VERSION 5.8 ;
BUSBITCHARS "[]" ;
DIVIDERCHAR "/" ;

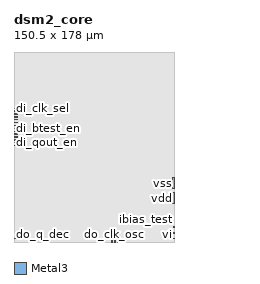
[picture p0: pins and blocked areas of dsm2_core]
MACRO dsm2_core
  CLASS BLOCK ;
  FOREIGN dsm2_core 0 0 ;
  ORIGIN 0 0 ;
  SIZE 150.5 BY 178 ;
  PIN di_btest_en
    DIRECTION INPUT ;
    USE SIGNAL ;
    PORT
      LAYER Metal3 ;
        RECT 0 106.305 3 106.595 ;
    END
  END di_btest_en
  PIN di_clk
    DIRECTION INPUT ;
    USE CLOCK ;
    PORT
      LAYER Metal3 ;
        RECT 97.125 0 97.415 1 ;
    END
  END di_clk
  PIN di_clk_sel
    DIRECTION INPUT ;
    USE SIGNAL ;
    PORT
      LAYER Metal3 ;
        RECT 0 125.135 3 125.425 ;
    END
  END di_clk_sel
  PIN di_dith_amp[0]
    DIRECTION INPUT ;
    USE SIGNAL ;
    PORT
      LAYER Metal3 ;
        RECT 0 103.615 3 103.905 ;
    END
  END di_dith_amp[0]
  PIN di_dith_amp[1]
    DIRECTION INPUT ;
    USE SIGNAL ;
    PORT
      LAYER Metal3 ;
        RECT 0 100.925 3 101.215 ;
    END
  END di_dith_amp[1]
  PIN di_dith_en
    DIRECTION INPUT ;
    USE SIGNAL ;
    PORT
      LAYER Metal3 ;
        RECT 0 98.235 3 98.525 ;
    END
  END di_dith_en
  PIN di_ena
    DIRECTION INPUT ;
    USE SIGNAL ;
    PORT
      LAYER Metal3 ;
        RECT 0 119.755 3 120.045 ;
    END
  END di_ena
  PIN di_osc_en
    DIRECTION INPUT ;
    USE SIGNAL ;
    PORT
      LAYER Metal3 ;
        RECT 0 122.445 3 122.735 ;
    END
  END di_osc_en
  PIN di_qout_en
    DIRECTION INPUT ;
    USE SIGNAL ;
    PORT
      LAYER Metal3 ;
        RECT 0 92.855 3 93.145 ;
    END
  END di_qout_en
  PIN di_rst_b
    DIRECTION INPUT ;
    USE SIGNAL ;
    PORT
      LAYER Metal3 ;
        RECT 0 95.545 3 95.835 ;
    END
  END di_rst_b
  PIN di_trim[0]
    DIRECTION INPUT ;
    USE SIGNAL ;
    PORT
      LAYER Metal3 ;
        RECT 0 117.065 3 117.355 ;
    END
  END di_trim[0]
  PIN di_trim[1]
    DIRECTION INPUT ;
    USE SIGNAL ;
    PORT
      LAYER Metal3 ;
        RECT 0 114.375 3 114.665 ;
    END
  END di_trim[1]
  PIN di_trim[2]
    DIRECTION INPUT ;
    USE SIGNAL ;
    PORT
      LAYER Metal3 ;
        RECT 0 111.685 3 111.975 ;
    END
  END di_trim[2]
  PIN di_trim[3]
    DIRECTION INPUT ;
    USE SIGNAL ;
    PORT
      LAYER Metal3 ;
        RECT 0 108.995 3 109.285 ;
    END
  END di_trim[3]
  PIN di_vcm_ext
    DIRECTION INPUT ;
    USE SIGNAL ;
    PORT
      LAYER Metal3 ;
        RECT 0 90.165 3 90.455 ;
    END
  END di_vcm_ext
  PIN do_clk_osc
    DIRECTION OUTPUT ;
    USE CLOCK ;
    PORT
      LAYER Metal3 ;
        RECT 94.435 0 94.725 1 ;
    END
  END do_clk_osc
  PIN do_osc_oe
    DIRECTION OUTPUT ;
    USE SIGNAL ;
    PORT
      LAYER Metal3 ;
        RECT 91.745 0 92.035 1 ;
    END
  END do_osc_oe
  PIN do_q
    DIRECTION OUTPUT ;
    USE SIGNAL ;
    PORT
      LAYER Metal3 ;
        RECT 99.815 0 100.105 1 ;
    END
  END do_q
  PIN do_q_b
    DIRECTION OUTPUT ;
    USE SIGNAL ;
    PORT
      LAYER Metal3 ;
        RECT 102.505 0 102.795 1 ;
    END
  END do_q_b
  PIN do_q_dec
    DIRECTION OUTPUT ;
    USE SIGNAL ;
    PORT
      LAYER Metal3 ;
        RECT 0 2.855 3 3.145 ;
    END
  END do_q_dec
  PIN ibias_test
    DIRECTION INOUT ;
    USE ANALOG ;
    PORT
      LAYER Metal3 ;
        RECT 149.5 13.855 150.5 14.145 ;
    END
  END ibias_test
  PIN vcm
    DIRECTION INOUT ;
    USE ANALOG ;
    PORT
      LAYER Metal3 ;
        RECT 149.5 8.355 150.5 8.645 ;
    END
  END vcm
  PIN vdd
    DIRECTION INOUT ;
    USE POWER ;
    PORT
      LAYER Metal3 ;
        RECT 148.5 36 150.5 46 ;
    END
  END vdd
  PIN vi
    DIRECTION INPUT ;
    USE ANALOG ;
    PORT
      LAYER Metal3 ;
        RECT 149.5 2.855 150.5 3.145 ;
    END
  END vi
  PIN vss
    DIRECTION INOUT ;
    USE GROUND ;
    PORT
      LAYER Metal3 ;
        RECT 148.5 50 150.5 60 ;
    END
  END vss
  OBS
    LAYER Metal1 ;
      RECT 0 0 150.5 178 ;
    LAYER Metal2 ;
      RECT 0 0 150.5 178 ;
    LAYER Metal3 ;
      RECT 0 0 90.745 1.855 ;
      RECT 93.035 0 93.435 2 ;
      RECT 95.725 0 96.125 2 ;
      RECT 98.415 0 98.815 2 ;
      RECT 101.105 0 101.505 2 ;
      RECT 103.795 0 150.5 1.855 ;
      RECT 4 1.855 90.745 2 ;
      RECT 103.795 1.855 148.5 2 ;
      RECT 4 2 148.5 4.145 ;
      RECT 0 4.145 150.5 7.355 ;
      RECT 0 7.355 148.5 9.645 ;
      RECT 0 9.645 150.5 12.855 ;
      RECT 0 12.855 148.5 15.145 ;
      RECT 0 15.145 150.5 35 ;
      RECT 0 35 147.5 47 ;
      RECT 0 47 150.5 49 ;
      RECT 0 49 147.5 61 ;
      RECT 0 61 150.5 89.165 ;
      RECT 4 89.165 150.5 91.455 ;
      RECT 0 91.455 150.5 91.855 ;
      RECT 4 91.855 150.5 94.145 ;
      RECT 0 94.145 150.5 94.545 ;
      RECT 4 94.545 150.5 96.835 ;
      RECT 0 96.835 150.5 97.235 ;
      RECT 4 97.235 150.5 99.525 ;
      RECT 0 99.525 150.5 99.925 ;
      RECT 4 99.925 150.5 102.215 ;
      RECT 0 102.215 150.5 102.615 ;
      RECT 4 102.615 150.5 104.905 ;
      RECT 0 104.905 150.5 105.305 ;
      RECT 4 105.305 150.5 107.595 ;
      RECT 0 107.595 150.5 107.995 ;
      RECT 4 107.995 150.5 110.285 ;
      RECT 0 110.285 150.5 110.685 ;
      RECT 4 110.685 150.5 112.975 ;
      RECT 0 112.975 150.5 113.375 ;
      RECT 4 113.375 150.5 115.665 ;
      RECT 0 115.665 150.5 116.065 ;
      RECT 4 116.065 150.5 118.355 ;
      RECT 0 118.355 150.5 118.755 ;
      RECT 4 118.755 150.5 121.045 ;
      RECT 0 121.045 150.5 121.445 ;
      RECT 4 121.445 150.5 123.735 ;
      RECT 0 123.735 150.5 124.135 ;
      RECT 4 124.135 150.5 126.425 ;
      RECT 0 126.425 150.5 178 ;
    LAYER Metal4 ;
      RECT 0 0 150.5 178 ;
  END
END dsm2_core

END LIBRARY
